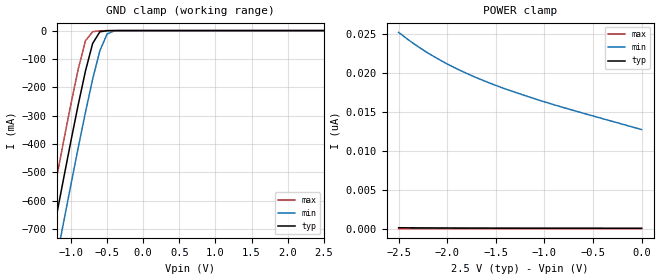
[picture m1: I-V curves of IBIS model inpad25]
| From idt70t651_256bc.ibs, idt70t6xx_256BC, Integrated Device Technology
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|in   nc   nc
|oe   nc   nc
| Note:
| 1. Pins B4 and R4 are nc for idt70t651, idt70t659, and idt70t658.
| 2. Pins B4 and R4 are nc for idt70t631, idt70t639.
| 3. Pins A4 and T4 are nc for idt70t659, idt70t658, and idt70t639.
| 4. Pins C4 and P4 are nc for idt70t658.
| 5. Pins A8, C8, P8, T8 are nc for x18 parts.
| 6. Pins B8 and R8 are UBLB and UBRB respectively for x18 parts.
| 7. Pins C9 and P9 are LBLB and LBRB respectively for x18 parts.
|   Model inpad25
[Model]   inpad25
Model_type   Input
Polarity   Non-Inverting
Vinl =  0.70000V
Vinh =  1.70000V
Vmeas =  1.25000V
C_comp   4.50000pF   4.50000pF   4.50000pF
[Temperature Range]   25.00000   100.00000   -40.00000
[Voltage Range]   2.50000V   2.30000V   2.70000V
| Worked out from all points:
|   GND clamp passes 1 mA (typ) near -0.52 V on its own axis
[GND_clamp]
| voltage   I(typ)   I(min)   I(max)
-2.5V     -2.438A    -2.587A    -2.312A
-1.4V     -921.5mA   -1.075A    -790.4mA
-1.3V     -786.2mA   -940.4mA   -654.7mA
-1.2V     -651.9mA   -806.3mA   -520.2mA
-1.1V     -519.1mA   -673.5mA   -387.5mA
-900mV    -262mA     -413.5mA   -136.1mA
-800mV    -143.3mA   -288.9mA   -36.33mA
-700mV    -45.49mA   -171.6mA   -3.972mA
-600mV    -4.309mA   -71.06mA   -834.5uA
-500mV    -411.8uA   -12.18mA   -82.9uA
-400mV    -35.7uA    -828.2uA   -3.321uA
2.5V      53.96pA    13.46nA    209.6fA
[POWER_clamp]
| voltage   I(typ)   I(min)   I(max)
-2.5V     115.4pA    25.27nA    455.8fA
-2.4V     107.8pA    24.31nA    438fA
-2.3V     101.2pA    23.43nA    421.7fA
-2.2V     95.32pA    22.62nA    405.4fA
-2.1V     90.21pA    21.89nA    391.5fA
-1.9V     81.83pA    20.57nA    366.6fA
-1.6V     72.81pA    18.93nA    335.5fA
-1.4V     68.5pA     17.98nA    318.8fA
-1V       62.48pA    16.33nA    288.4fA
-600mV    58.51pA    14.86nA    261.9fA
0V        53.96pA    12.76nA    222.8fA
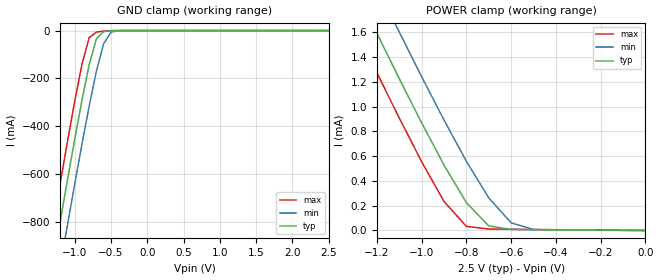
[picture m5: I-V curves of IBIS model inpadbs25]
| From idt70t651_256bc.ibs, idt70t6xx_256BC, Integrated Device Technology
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|   Model inpadbs25
[Model]   inpadbs25
Model_type   Input
Polarity   Non-Inverting
Vinl =  0.80000V
Vinh =  2.00000V
Vmeas =  1.50000V
C_comp   4.50000pF   4.50000pF   4.50000pF
[Temperature Range]   25.00000   100.00000   -40.00000
[Voltage Range]   2.50000V   2.20000V   2.80000V
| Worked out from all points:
|   GND clamp passes 1 mA (typ) near -0.51 V on its own axis
|   POWER clamp passes 1 mA (typ) near -1.04 V on its own axis
[GND_clamp]
| voltage   I(typ)   I(min)   I(max)
-2.5V     -3.145A    -3.326A    -2.992A
-1.4V     -1.152A    -1.34A     -992.6mA
-1.3V     -975mA     -1.163A    -814.6mA
-1.2V     -799.1mA   -987.7mA   -638.4mA
-1.1V     -625.5mA   -813.9mA   -465mA
-900mV    -292mA     -475.5mA   -141.4mA
-800mV    -142.5mA   -315.2mA   -29.67mA
-700mV    -33.98mA   -168.4mA   -6.426mA
-600mV    -4.297mA   -54.25mA   -1.776mA
-500mV    -774.3uA   -6.916mA   -201.4uA
-400mV    -82.6uA    -641.8uA   -19.34uA
2.5V      493.8pA    2.51uA     -3.968uA
[POWER_clamp]
| voltage   I(typ)   I(min)   I(max)
-2.5V     6.547mA    6.907mA    6.245mA
-1.3V     1.963mA    2.338mA    1.645mA
-1.2V     1.592mA    1.967mA    1.273mA
-1.1V     1.226mA    1.601mA    907.8uA
-1V       868.8uA    1.241mA    555.1uA
-900mV    528.1uA    891.2uA    233.9uA
-800mV    224.6uA    558.4uA    32.77uA
-700mV    36.91uA    262.8uA    11.77uA
-600mV    8.091uA    61.72uA    9.83uA
-500mV    6.002uA    8.231uA    8.09uA
0V        493.8pA    37.64nA    3.402pA
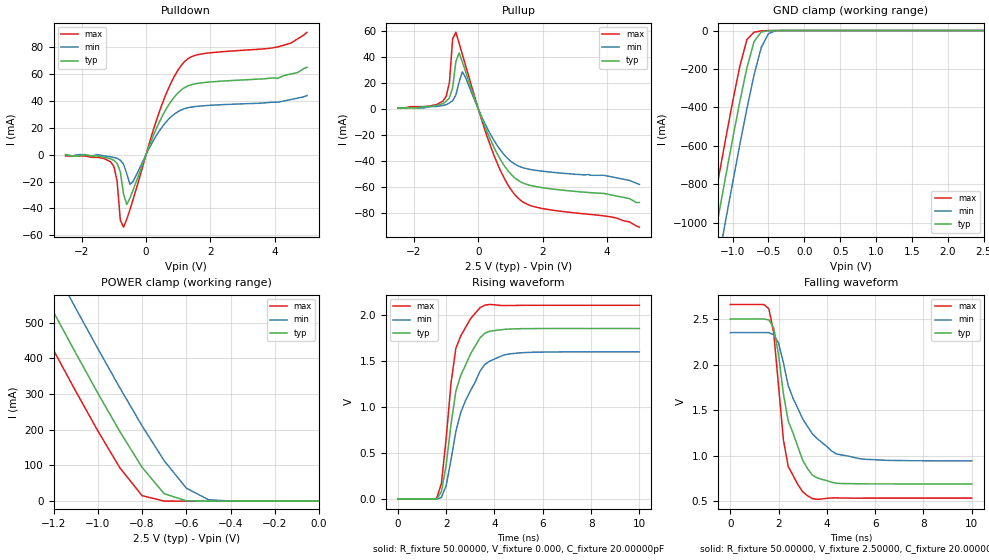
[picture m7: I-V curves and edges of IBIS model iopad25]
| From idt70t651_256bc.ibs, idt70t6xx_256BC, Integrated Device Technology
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|   Model iopad25
[Model]   iopad25
Model_type   I/O
Polarity   Non-Inverting
Enable   Active-Low
Vinl =  0.70000V
Vinh =  1.70000V
Vmeas =  1.25000V
C_comp   4.50000pF   4.50000pF   4.50000pF
[Temperature Range]   25.00000   100.00000   -40.00000
[Voltage Range]   2.50000V   2.30000V   2.70000V
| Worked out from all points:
|   slope of the pulldown table from 0 to 0.375 V, typ, clamps not added: 16.8 ohm
|   slope of the pullup table from 0 to 0.375 V, typ, clamps not added: 15.9 ohm
|   GND clamp passes 1 mA (typ) near -0.50 V on its own axis
|   POWER clamp passes 1 mA (typ) near -0.60 V on its own axis
|   rising waveform, R_fixture 50.00000, V_fixture 0.000, C_fixture 20.00000pF: 20-80 % time 849ps typ, 1.09ns min, 567ps max; typ from 0 V to 1.85 V
|   falling waveform, R_fixture 50.00000, V_fixture 2.50000, C_fixture 20.00000pF: 20-80 % time 881ps typ, 1.31ns min, 508ps max; typ from 2.5 V to 0.688 V
[Pulldown]
| voltage   I(typ)   I(min)   I(max)
-2.5V     0A         0A         -1mA
-1.1V     -3.1mA     -1.6mA     -5.4mA
-1V       -4.2mA     -2.1mA     -8.8mA
-900mV    -6.6mA     -2.8mA     -19.7mA
-800mV    -12.8mA    -4.1mA     -48.76mA
-700mV    -29.43mA   -7mA       -53.96mA
-600mV    -37.03mA   -14.17mA   -48.13mA
-500mV    -32.29mA   -22.11mA   -40.89mA
500mV     28.49mA    20.63mA    37.7mA
1.2V      49.93mA    34.24mA    69.32mA
4.1V      56.9mA     39mA       80.2mA
5V        65mA       44mA       91mA
[Pullup]
| voltage   I(typ)   I(min)   I(max)
-2.5V     1mA        1mA        1mA
-1.1V     4.3mA      2.9mA      6.3mA
-900mV    8.9mA      4.8mA      20.66mA
-800mV    16.52mA    6.6mA      54.26mA
-700mV    36.86mA    11mA       59.33mA
-600mV    43.46mA    20.89mA    50.96mA
-500mV    36.57mA    28.78mA    42.4mA
400mV     -24.99mA   -20.52mA   -30.09mA
800mV     -43.39mA   -35.12mA   -53.17mA
1.2V      -54.33mA   -43.34mA   -67.83mA
1.8V      -59.77mA   -47.2mA    -75.63mA
5V        -72mA      -58mA      -91mA
[GND_clamp]
| voltage   I(typ)   I(min)   I(max)
-2.5V     -3.74A     -3.961A    -3.553A
-1.4V     -1.389A    -1.618A    -1.194A
-1.3V     -1.179A    -1.409A    -984.4mA
-1.2V     -972.3mA   -1.201A    -776.5mA
-1.1V     -767.3mA   -996.6mA   -571.8mA
-900mV    -372.8mA   -596.6mA   -188mA
-800mV    -194.3mA   -406.4mA   -47.16mA
-700mV    -57.22mA   -230.7mA   -8.4mA
-600mV    -7.393mA   -88.33mA   -2.169mA
-500mV    -1.009mA   -16.09mA   -229.2uA
-400mV    -92.71uA   -1.476mA   -9.663uA
2.5V      510.3pA    625.2nA    1.837pA
[POWER_clamp]
| voltage   I(typ)   I(min)   I(max)
-2.5V     2.074A     2.195A     1.972A
-1.4V     762.2mA    887.1mA    656mA
-1.3V     645.3mA    770.5mA    538.7mA
-1.2V     529.4mA    654.8mA    422.5mA
-1.1V     414.9mA    540.2mA    308.1mA
-1V       302.5mA    427.3mA    196.9mA
-900mV    194.4mA    316.8mA    93.14mA
-800mV    94.88mA    210.9mA    15.33mA
-700mV    20.78mA    113.2mA    204uA
-600mV    865.9uA    36.42mA    1.94uA
-500mV    23.06uA    3.99mA     31.75nA
0V        510.3pA    46.37nA    1.885pA
[Ramp]
| variable   typ   min   max
dV/dt_r   1.11300/0.34369n   0.96060/0.43779n   1.26420/0.27148n
dV/dt_f   1.08936/0.31359n   0.87954/0.39756n   1.27392/0.24900n
R_load = 50.00000
[Rising Waveform]
R_fixture = 50.00000
V_fixture = 0.000
C_fixture = 20.00000pF
R_dut = 0.16200
L_dut = 4.82000nH
C_dut = 1.47000pF
| time   V(typ)   V(min)   V(max)
0s        0V         0V         0V
1.6ns     1.077mV    -2.179mV   4.788mV
1.8ns     79.09mV    19.13mV    169.1mV
2ns       373.5mV    147.9mV    663.3mV
2.2ns     814.6mV    428.3mV    1.261V
2.4ns     1.171V     735.9mV    1.636V
2.8ns     1.453V     1.069V     1.861V
3.4ns     1.749V     1.387V     2.075V
4.6ns     1.844V     1.574V     2.099V
10ns      1.85V      1.597V     2.102V
[Falling Waveform]
R_fixture = 50.00000
V_fixture = 2.50000
C_fixture = 20.00000pF
R_dut = 0.16200
L_dut = 4.82000nH
C_dut = 1.47000pF
| time   V(typ)   V(min)   V(max)
0s        2.5V       2.351V     2.66V
1.6ns     2.49V      2.35V      2.612V
1.8ns     2.403V     2.328V     2.349V
2ns       2.111V     2.236V     1.766V
2.2ns     1.681V     2.022V     1.176V
2.4ns     1.381V     1.77V      879.6mV
3.2ns     857.3mV    1.32V      558.6mV
3.6ns     753.9mV    1.186V     518.8mV
4.4ns     695.4mV    1.018V     534.6mV
10ns      688.2mV    941.8mV    532.5mV
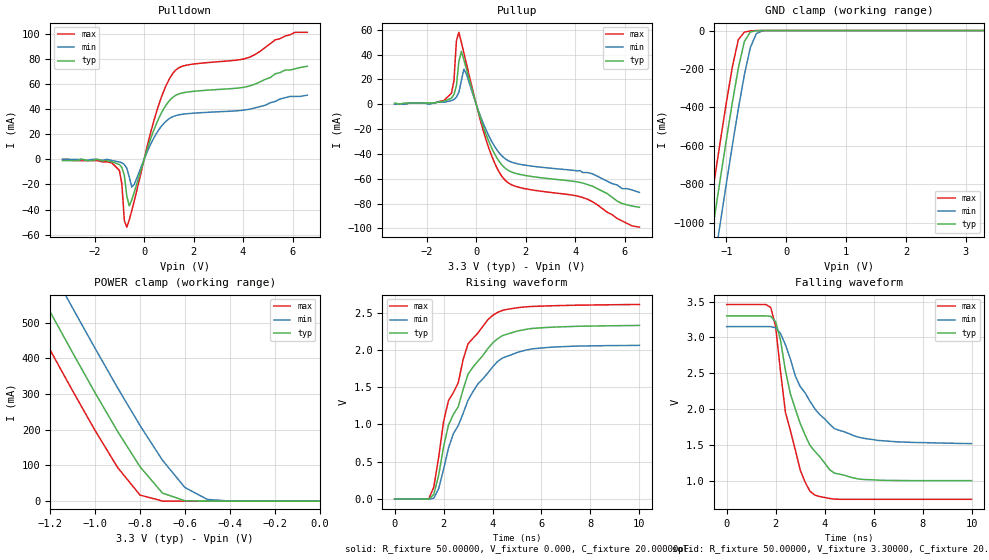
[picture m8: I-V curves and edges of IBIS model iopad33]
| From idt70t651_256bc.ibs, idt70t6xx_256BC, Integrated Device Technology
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|   Model iopad33
[Model]   iopad33
Model_type   I/O
Polarity   Non-Inverting
Enable   Active-Low
Vinl =  0.80000V
Vinh =  2.00000V
Vmeas =  1.50000V
C_comp   4.50000pF   4.50000pF   4.50000pF
[Temperature Range]   25.00000   100.00000   -40.00000
[Voltage Range]   3.30000V   3.10000V   3.50000V
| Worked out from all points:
|   slope of the pulldown table from 0 to 0.495 V, typ, clamps not added: 17.5 ohm
|   slope of the pullup table from 0 to 0.495 V, typ, clamps not added: 16.9 ohm
|   GND clamp passes 1 mA (typ) near -0.50 V on its own axis
|   POWER clamp passes 1 mA (typ) near -0.59 V on its own axis
|   rising waveform, R_fixture 50.00000, V_fixture 0.000, C_fixture 20.00000pF: 20-80 % time 1.56ns typ, 1.69ns min, 1.23ns max; typ from 0 V to 2.33 V
|   falling waveform, R_fixture 50.00000, V_fixture 3.30000, C_fixture 20.00000pF: 20-80 % time 1.22ns typ, 1.58ns min, 833ps max; typ from 3.3 V to 1 V
[Pulldown]
| voltage   I(typ)   I(min)   I(max)
-3.3V     -1mA       0A         0A
-1.5V     -1mA       0A         -2mA
-1V       -4.2mA     -2.1mA     -8.8mA
-900mV    -6.6mA     -2.8mA     -19.7mA
-800mV    -12.8mA    -4.1mA     -48.76mA
-700mV    -29.43mA   -7mA       -53.96mA
-600mV    -37.03mA   -14.17mA   -48.13mA
-500mV    -32.29mA   -22.11mA   -40.89mA
500mV     28.49mA    20.63mA    37.7mA
1.2V      49.93mA    34.24mA    69.32mA
4.1V      57.54mA    39.4mA     80.21mA
6.6V      74mA       51mA       101mA
[Pullup]
| voltage   I(typ)   I(min)   I(max)
-3.3V     1mA        0A         0A
-1.7V     1mA        1mA        1mA
-1V       4.9mA      2.9mA      8.9mA
-900mV    7.8mA      3.9mA      18.89mA
-800mV    14.94mA    5.7mA      51.34mA
-700mV    34.57mA    9.6mA      57.95mA
-600mV    42.62mA    19.25mA    49.81mA
-500mV    36.06mA    28.2mA     41.39mA
400mV     -24.39mA   -20.73mA   -28.72mA
1.1V      -50.2mA    -42.72mA   -59.63mA
4.3V      -63.4mA    -55mA      -75.04mA
6.6V      -83mA      -71mA      -99mA
[GND_clamp]
| voltage   I(typ)   I(min)   I(max)
-3.3V     -5.469A    -5.686A    -5.287A
-1.4V     -1.389A    -1.618A    -1.194A
-1.3V     -1.179A    -1.409A    -984.5mA
-1.2V     -972.3mA   -1.201A    -776.5mA
-1.1V     -767.3mA   -996.6mA   -571.8mA
-900mV    -372.8mA   -596.6mA   -188.1mA
-800mV    -194.3mA   -406.4mA   -47.16mA
-700mV    -57.22mA   -230.7mA   -8.4mA
-600mV    -7.393mA   -88.33mA   -2.169mA
-500mV    -1.009mA   -16.09mA   -229.2uA
-400mV    -92.71uA   -1.476mA   -9.663uA
3.3V      525.2pA    638.3nA    1.93pA
[POWER_clamp]
| voltage   I(typ)   I(min)   I(max)
-3.3V     3.039A     3.158A     2.94A
-1.4V     762.6mA    887.5mA    656.3mA
-1.3V     645.8mA    771mA      539.1mA
-1.2V     529.9mA    655.3mA    422.9mA
-1.1V     415.5mA    540.8mA    308.7mA
-1V       303.3mA    427.9mA    197.7mA
-900mV    195.4mA    317.6mA    94.31mA
-800mV    96.26mA    211.9mA    16.94mA
-700mV    22.53mA    114.6mA    305uA
-600mV    1.137mA    38.18mA    3.7uA
-500mV    27.9uA     4.729mA    76.79nA
0V        525.2pA    48.85nA    2.005pA
[Ramp]
| variable   typ   min   max
dV/dt_r   1.40040/0.58697n   1.23900/0.67661n   1.57020/0.47445n
dV/dt_f   1.38174/0.37674n   1.05360/0.46010n   1.62528/0.29291n
R_load = 50.00000
[Rising Waveform]
R_fixture = 50.00000
V_fixture = 0.000
C_fixture = 20.00000pF
R_dut = 0.16200
L_dut = 4.82000nH
C_dut = 1.47000pF
| time   V(typ)   V(min)   V(max)
0s        0V         0V         0V
1.4ns     -2.825mV   -4.703mV   5.134mV
1.6ns     61.27mV    10.9mV     157.9mV
1.8ns     317.3mV    139.1mV    559.5mV
2.2ns     990.5mV    682.2mV    1.319V
2.6ns     1.238V     984.8mV    1.56V
3ns       1.674V     1.324V     2.081V
4ns       2.091V     1.77V      2.461V
5.6ns     2.287V     2.013V     2.582V
10ns      2.327V     2.06V      2.608V
[Falling Waveform]
R_fixture = 50.00000
V_fixture = 3.30000
C_fixture = 20.00000pF
R_dut = 0.16200
L_dut = 4.82000nH
C_dut = 1.47000pF
| time   V(typ)   V(min)   V(max)
0s        3.3V       3.15V      3.459V
1.8ns     3.293V     3.15V      3.417V
2ns       3.218V     3.133V     3.147V
2.2ns     2.958V     3.054V     2.522V
2.4ns     2.536V     2.897V     1.954V
3ns       1.802V     2.316V     1.155V
3.6ns     1.411V     2.003V     799.2mV
4.4ns     1.106V     1.727V     743.3mV
5.4ns     1.023V     1.606V     741mV
10ns      1.001V     1.518V     740.5mV
